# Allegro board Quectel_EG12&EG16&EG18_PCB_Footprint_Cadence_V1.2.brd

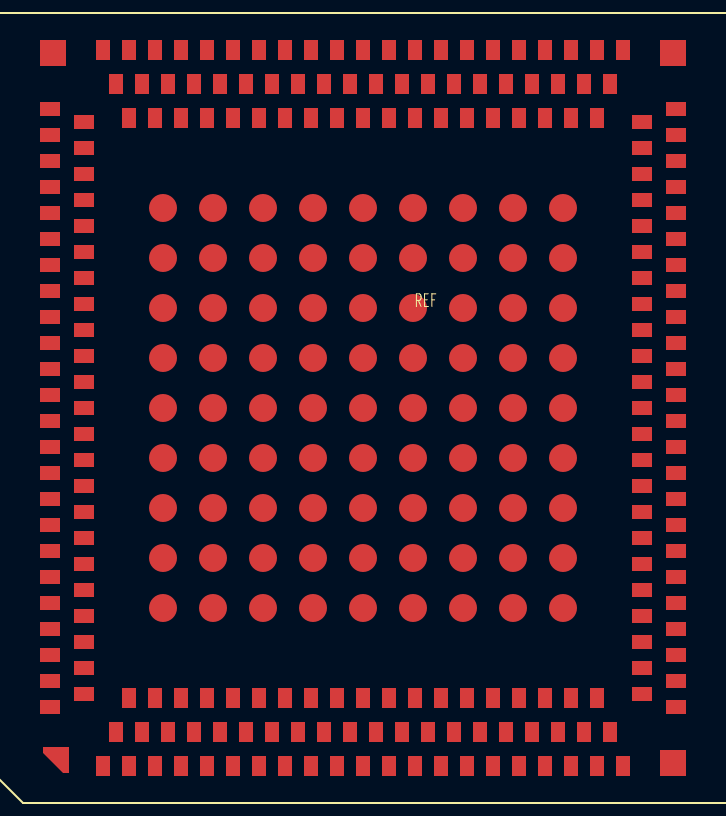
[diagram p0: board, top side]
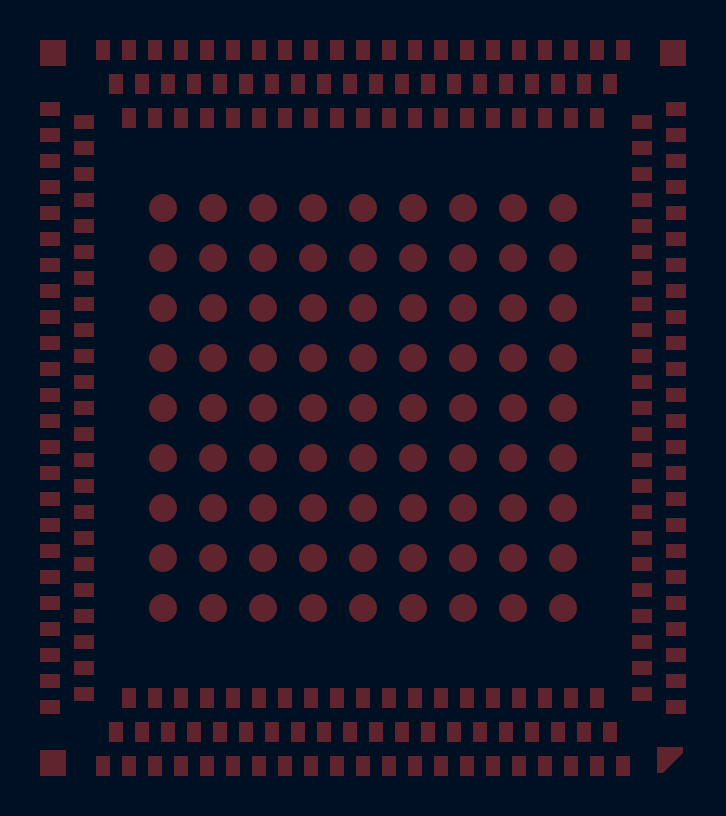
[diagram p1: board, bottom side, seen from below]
No outline. copper layers: TOP, BOTTOM. Coordinates in mm from the lowest, leftmost part position.

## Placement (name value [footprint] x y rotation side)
REF  -  [unnamed]  0 0 0 top

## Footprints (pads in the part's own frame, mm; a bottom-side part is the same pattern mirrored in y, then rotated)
unnamed
  rect 0.7x1 smd: 1(-13,-17.9) 2(-12.35,-16.2) 3(-11.7,-17.9) 4(-11.05,-16.2) 5(-10.4,-17.9) 6(-9.75,-16.2) 7(-9.1,-17.9) 8(-8.45,-16.2) 9(-7.8,-17.9) 10(-7.15,-16.2) 11(-6.5,-17.9) 12(-5.85,-16.2) 13(-5.2,-17.9) 14(-4.55,-16.2) 15(-3.9,-17.9) 16(-3.25,-16.2) 17(-2.6,-17.9) 18(-1.95,-16.2) 19(-1.3,-17.9) 20(-0.65,-16.2) 21(0,-17.9) 22(0.65,-16.2) 23(1.3,-17.9) 24(1.95,-16.2) 25(2.6,-17.9) 26(3.25,-16.2) 27(3.9,-17.9) 28(4.55,-16.2) 29(5.2,-17.9) 30(5.85,-16.2) 31(6.5,-17.9) 32(7.15,-16.2) 33(7.8,-17.9) 34(8.45,-16.2) 35(9.1,-17.9) 36(9.75,-16.2) 37(10.4,-17.9) 38(11.05,-16.2) 39(11.7,-17.9) 40(12.35,-16.2) 41(13,-17.9) 89(13,17.9) 90(12.35,16.2) 91(11.7,17.9) 92(11.05,16.2) 93(10.4,17.9) 94(9.75,16.2) 95(9.1,17.9) 96(8.45,16.2) 97(7.8,17.9) 98(7.15,16.2) 99(6.5,17.9) 100(5.85,16.2) 101(5.2,17.9) 102(4.55,16.2) 103(3.9,17.9) 104(3.25,16.2) 105(2.6,17.9) 106(1.95,16.2) 107(1.3,17.9) 108(0.65,16.2) 109(0,17.9) 110(-0.65,16.2) 111(-1.3,17.9) 112(-1.95,16.2) 113(-2.6,17.9) 114(-3.25,16.2) 115(-3.9,17.9) 116(-4.55,16.2) 117(-5.2,17.9) 118(-5.85,16.2) 119(-6.5,17.9) 120(-7.15,16.2) 121(-7.8,17.9) 122(-8.45,16.2) 123(-9.1,17.9) 124(-9.75,16.2) 125(-10.4,17.9) 126(-11.05,16.2) 127(-11.7,17.9) 128(-12.35,16.2) 129(-13,17.9) 177(-11.7,-14.5) 178(-10.4,-14.5) 179(-9.1,-14.5) 180(-7.8,-14.5) 181(-6.5,-14.5) 182(-5.2,-14.5) 183(-3.9,-14.5) 184(-2.6,-14.5) 185(-1.3,-14.5) 186(0,-14.5) 187(1.3,-14.5) 188(2.6,-14.5) 189(3.9,-14.5) 190(5.2,-14.5) 191(6.5,-14.5) 192(7.8,-14.5) 193(9.1,-14.5) 194(10.4,-14.5) 195(11.7,-14.5) 196(11.7,14.5) 197(10.4,14.5) 198(9.1,14.5) 199(7.8,14.5) 200(6.5,14.5) 201(5.2,14.5) 202(3.9,14.5) 203(2.6,14.5) 204(1.3,14.5) 205(0,14.5) 206(-1.3,14.5) 207(-2.6,14.5) 208(-3.9,14.5) 209(-5.2,14.5) 210(-6.5,14.5) 211(-7.8,14.5) 212(-9.1,14.5) 213(-10.4,14.5) 214(-11.7,14.5)
  rect 1x0.7 smd: 42(15.65,-14.95) 43(13.95,-14.3) 44(15.65,-13.65) 45(13.95,-13) 46(15.65,-12.35) 47(13.95,-11.7) 48(15.65,-11.05) 49(13.95,-10.4) 50(15.65,-9.75) 51(13.95,-9.1) 52(15.65,-8.45) 53(13.95,-7.8) 54(15.65,-7.15) 55(13.95,-6.5) 56(15.65,-5.85) 57(13.95,-5.2) 58(15.65,-4.55) 59(13.95,-3.9) 60(15.65,-3.25) 61(13.95,-2.6) 62(15.65,-1.95) 63(13.95,-1.3) 64(15.65,-0.65) 65(13.95,0) 66(15.65,0.65) 67(13.95,1.3) 68(15.65,1.95) 69(13.95,2.6) 70(15.65,3.25) 71(13.95,3.9) 72(15.65,4.55) 73(13.95,5.2) 74(15.65,5.85) 75(13.95,6.5) 76(15.65,7.15) 77(13.95,7.8) 78(15.65,8.45) 79(13.95,9.1) 80(15.65,9.75) 81(13.95,10.4) 82(15.65,11.05) 83(13.95,11.7) 84(15.65,12.35) 85(13.95,13) 86(15.65,13.65) 87(13.95,14.3) 88(15.65,14.95) 130(-15.65,14.95) 131(-13.95,14.3) 132(-15.65,13.65) 133(-13.95,13) 134(-15.65,12.35) 135(-13.95,11.7) 136(-15.65,11.05) 137(-13.95,10.4) 138(-15.65,9.75) 139(-13.95,9.1) 140(-15.65,8.45) 141(-13.95,7.8) 142(-15.65,7.15) 143(-13.95,6.5) 144(-15.65,5.85) 145(-13.95,5.2) 146(-15.65,4.55) 147(-13.95,3.9) 148(-15.65,3.25) 149(-13.95,2.6) 150(-15.65,1.95) 151(-13.95,1.3) 152(-15.65,0.65) 153(-13.95,0) 154(-15.65,-0.65) 155(-13.95,-1.3) 156(-15.65,-1.95) 157(-13.95,-2.6) 158(-15.65,-3.25) 159(-13.95,-3.9) 160(-15.65,-4.55) 161(-13.95,-5.2) 162(-15.65,-5.85) 163(-13.95,-6.5) 164(-15.65,-7.15) 165(-13.95,-7.8) 166(-15.65,-8.45) 167(-13.95,-9.1) 168(-15.65,-9.75) 169(-13.95,-10.4) 170(-15.65,-11.05) 171(-13.95,-11.7) 172(-15.65,-12.35) 173(-13.95,-13) 174(-15.65,-13.65) 175(-13.95,-14.3) 176(-15.65,-14.95)
  round 1.4 smd: 215(-10,10) 216(-7.5,10) 217(-5,10) 218(-2.5,10) 219(0,10) 220(2.5,10) 221(5,10) 222(7.5,10) 223(10,10) 224(-10,7.5) 225(-7.5,7.5) 226(-5,7.5) 227(-2.5,7.5) 228(0,7.5) 229(2.5,7.5) 230(5,7.5) 231(7.5,7.5) 232(10,7.5) 233(-10,5) 234(-7.5,5) 235(-5,5) 236(-2.5,5) 237(0,5) 238(2.5,5) 239(5,5) 240(7.5,5) 241(10,5) 242(-10,2.5) 243(-7.5,2.5) 244(-5,2.5) 245(-2.5,2.5) 246(0,2.5) 247(2.5,2.5) 248(5,2.5) 249(7.5,2.5) 250(10,2.5) 251(-10,0) 252(-7.5,0) 253(-5,0) 254(-2.5,0) 255(0,0) 256(2.5,0) 257(5,0) 258(7.5,0) 259(10,0) 260(-10,-2.5) 261(-7.5,-2.5) 262(-5,-2.5) 263(-2.5,-2.5) 264(0,-2.5) 265(2.5,-2.5) 266(5,-2.5) 267(7.5,-2.5) 268(10,-2.5) 269(-10,-5) 270(-7.5,-5) 271(-5,-5) 272(-2.5,-5) 273(0,-5) 274(2.5,-5) 275(5,-5) 276(7.5,-5) 277(10,-5) 278(-10,-7.5) 279(-7.5,-7.5) 280(-5,-7.5) 281(-2.5,-7.5) 282(0,-7.5) 283(2.5,-7.5) 284(5,-7.5) 285(7.5,-7.5) 286(10,-7.5) 287(-10,-10) 288(-7.5,-10) 289(-5,-10) 290(-2.5,-10) 291(0,-10) 292(2.5,-10) 293(5,-10) 294(7.5,-10) 295(10,-10)
  custom 0.325x0.325 smd: 296(-15.35,-17.6)
  rect 1.3x1.3 smd: 297(15.5,-17.75) 298(15.5,17.75) 299(-15.5,17.75)

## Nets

Pads without a net: REF 1 2 3 4 5 6 7 8 9 10 11 12 13 14 15 16 17 18 19 20 21 22 23 24 25 26 27 28 29 30 31 32 33 34 35 36 37 38 39 40 41 42 43 44 45 46 47 48 49 50 51 52 53 54 55 56 57 58 59 60 61 62 63 64 65 66 67 68 69 70 71 72 73 74 75 76 77 78 79 80 81 82 83 84 85 86 87 88 89 90 91 92 93 94 95 96 97 98 99 100 101 102 103 104 105 106 107 108 109 110 111 112 113 114 115 116 117 118 119 120 121 122 123 124 125 126 127 128 129 130 131 132 133 134 135 136 137 138 139 140 141 142 143 144 145 146 147 148 149 150 151 152 153 154 155 156 157 158 159 160 161 162 163 164 165 166 167 168 169 170 171 172 173 174 175 176 177 178 179 180 181 182 183 184 185 186 187 188 189 190 191 192 193 194 195 196 197 198 199 200 201 202 203 204 205 206 207 208 209 210 211 212 213 214 215 216 217 218 219 220 221 222 223 224 225 226 227 228 229 230 231 232 233 234 235 236 237 238 239 240 241 242 243 244 245 246 247 248 249 250 251 252 253 254 255 256 257 258 259 260 261 262 263 264 265 266 267 268 269 270 271 272 273 274 275 276 277 278 279 280 281 282 283 284 285 286 287 288 289 290 291 292 293 294 295 296 297 298 299
